VERSION 5.8 ;
BUSBITCHARS "[]" ;
DIVIDERCHAR "/" ;

UNITS
  DATABASE MICRONS 1000 ;
END UNITS

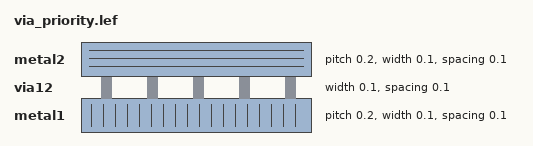
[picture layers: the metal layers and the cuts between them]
LAYER metal1
  TYPE ROUTING ;
  DIRECTION VERTICAL ;
  PITCH 0.2 ;
  WIDTH 0.1 ;
  SPACING 0.1 ;
  AREA 0.02 ;
END metal1

LAYER via12
  TYPE CUT ;
  SPACING 0.1 ;
  WIDTH 0.1 ;
END via12

LAYER metal2
  TYPE ROUTING ;
  DIRECTION HORIZONTAL ;
  PITCH 0.2 ;
  WIDTH 0.1 ;
  SPACING 0.1 ;
  AREA 0.02 ;
END metal2

# Two vias for the metal1/metal2 pair, neither marked OR_DEFAULT. The larger
# one is declared first, so a db-order pick would take it; the priority ranking
# must instead choose VIA_SMALL (smaller enclosure).
VIA VIA_BIG
  LAYER metal1 ;
    RECT -0.1 -0.15 0.1 0.15 ;
  LAYER via12 ;
    RECT -0.05 -0.05 0.05 0.05 ;
  LAYER metal2 ;
    RECT -0.15 -0.1 0.15 0.1 ;
END VIA_BIG

VIA VIA_SMALL
  LAYER metal1 ;
    RECT -0.05 -0.075 0.05 0.075 ;
  LAYER via12 ;
    RECT -0.05 -0.05 0.05 0.05 ;
  LAYER metal2 ;
    RECT -0.075 -0.05 0.075 0.05 ;
END VIA_SMALL

END LIBRARY
